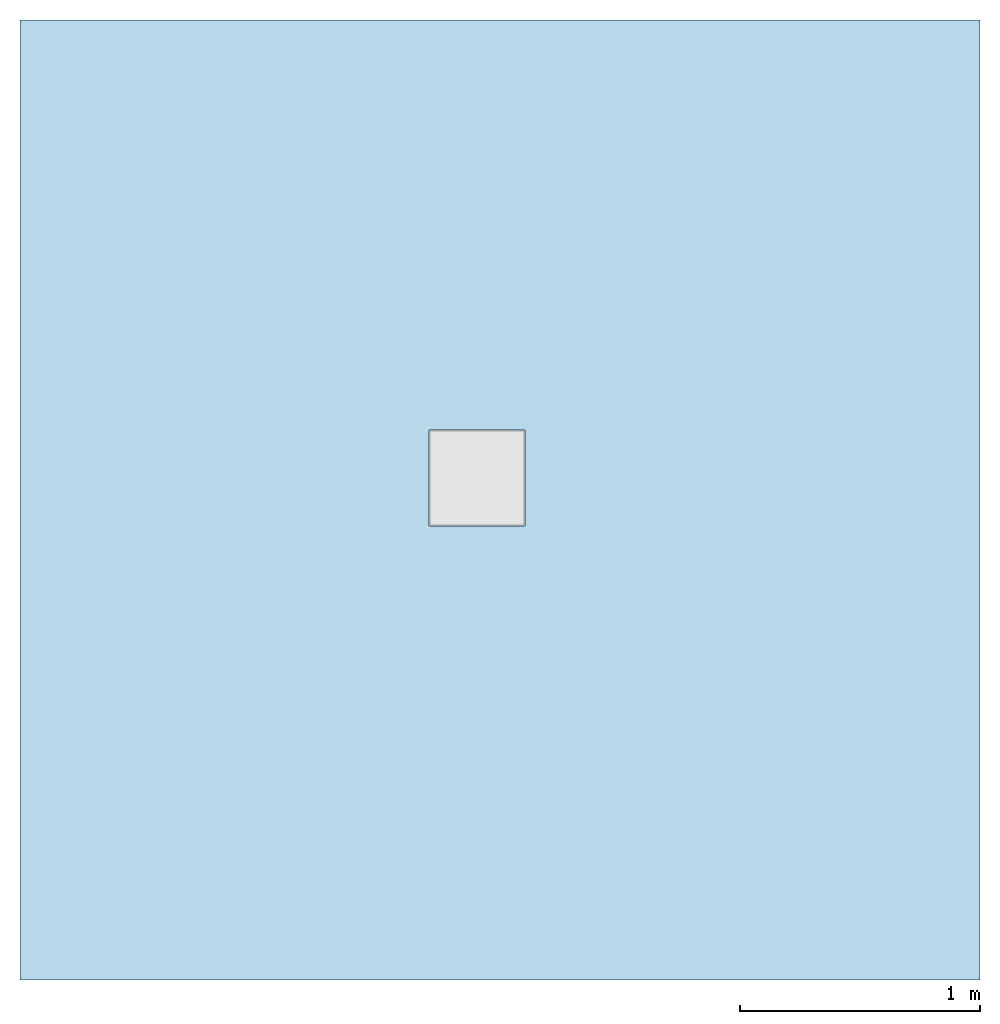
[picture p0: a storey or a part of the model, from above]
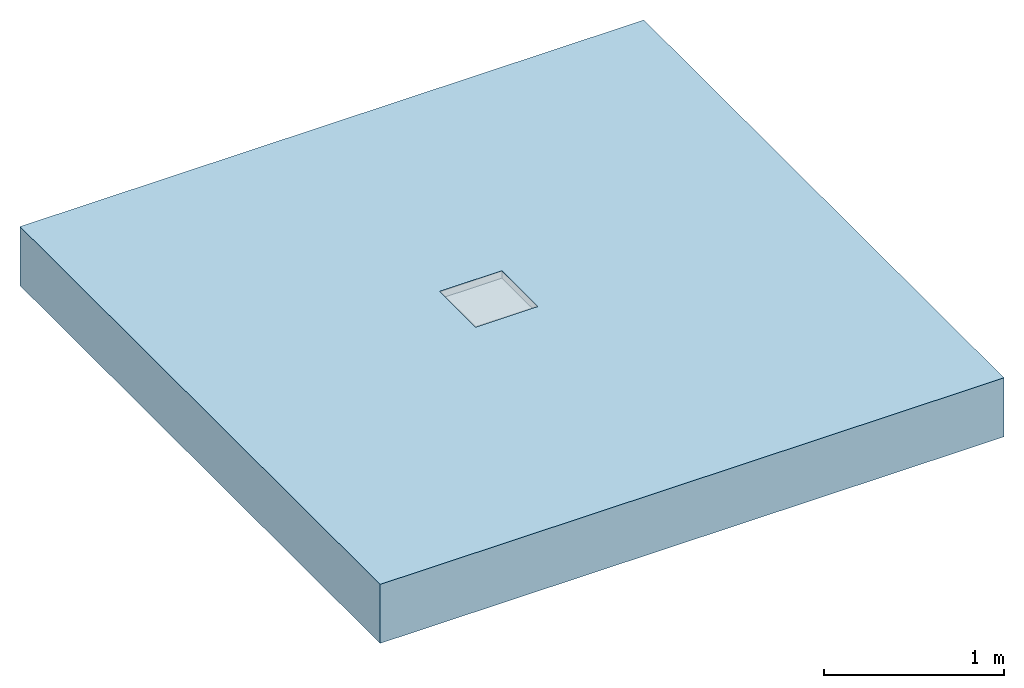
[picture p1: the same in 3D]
Properties of the parts of a building model (IFC2X3)

# File
Description: ViewDefinition [CoordinationView]
File name: Project Number
Time: 2014-06-06T10:56:56
Written by: The EXPRESS Data Manager Version 5.01.0100.02.64mod : 6 Jun 2012
Made in: 20130308_1515(x64) - Exporter 2014.0.2013.0308 - Default UI
Comment: STEP Physical File produced by: The EXPRESS Data Manager Version 5.01.0100.02.64mod : 6 Jun 2012 * Module: EDMstepFileFactory/EDMstandAlone * Creation date: Fri Jun 06 10:56:56 2014 * Host: IN-BLR-PC-0010 * Database: C:\Users\palleri\AppData\Local\Temp\{E2782E1B-111F-43A8-B7EB-C710C4CADA0F}\ifc * Database version: 5507 * Database creation date: Fri Jun 06 10:56:55 2014 * Schema: IFC2X3 * Model: DataRepository.ifc * Model creation date: Fri Jun 06 10:56:56 2014 * Header model: DataRepository.ifc_HeaderModel * Header model creation date: Fri Jun 06 10:56:56 2014 * EDMuser: sdai-user * EDMgroup: sdai-group * License ID and type: 5605 : Permanent license. Expiry date: * EDMstepFileFactory options: 020000

# IfcProject, Project Number
LongName: Project Name; Phase: Project Status

# IfcSite, Default
RefLatitude: 42, 21, 30, 344238; RefLongitude: -71, -3, -35, -194702; RefElevation: 0 mm

# IfcBuilding
Pset_BuildingCommon - NumberOfStoreys: 1
Other - Client Name: Owner; Project Name: Project Name; Project Status: Project Status; Project Address: ## Street City, State Zip; Project Issue Date: Issue Date; Project Number: Project Number

# IfcBuildingStorey, Level 1
LongName: Level 1; Elevation: 0 mm
Constraints - Elevation Base: Project Base Point; Elevation: 0 mm
Graphics - Color: 0; Symbol: M_Level Head - Circle: M_Level Head - Circle; Symbol at End 1 Default: no; Line Pattern: Center; Line Weight: 1; Symbol at End 2 Default: yes
Identity Data - Name: Level 1; Building Story: yes; Structural: no
Dimensions - Computation Height: 0 mm

# IfcFlowTerminal: 38150 - Access Frame - Fixed Height - Invert Depth 50mm, ACO Freedeck Access Frame & Drain Duct (Accessories part 1) V1.27 - GS:38150 - Access Frame - Fixed Height - Invert Depth 50mm:276243
In: Level 1
Material: Galvanized Steel
Dimensions - Top Void Height End: -50 mm; Height for Adjustable Access Frame: 105 mm; Drainage Duct – Level below FFL: 30 mm; Top Void Height Start: 2 mm; Total Height: 105 mm; Access Frame Extension Position Height: 5000 mm; Base Height: 3000 mm; Drain Duct End: -100 mm; Grating Start: 0 mm; Grating End: -20 mm
Construction - 36754_Access Grating_Mesh Grating_Galvanized Steel: yes; 38687_Access Frame Extension_Galvanized Steel_Invert Depth 75mm: no; 38685_Access Frame Extension_Galvanized Steel_Invert Depth 50mm: no
Phasing - Phase Created: New Construction
Identity Data - Mark: 14; E-mail Technical: abdtechnical@aco.co.uk; Watermark2: This file is water marked and users are prohibited to reproduce, adapt, distribute this information; Website: www.acobd.com; Watermarked By: www.acobd.com; E-mail Sales: abdcommercial@aco.co.uk; Watermark1: This file is the property of ACO Technologies PLC; Manufacturer: ACO Building Drainage; Watermarked With: BIM Manager Premium Suite; Telephone: +44 (0)1462 816666; Address: ACO Business Centre, Caxton Road, Bedford, MK41 0LF; Fax: +44 (0)1462 851490
Other - Access Frame Extension Height: 50 mm; Drain Duct Vertical Height: 5000 mm; Access Frame Extension: no; Extension Removal Void: -2 mm; Adjustable Access Frame Position Height: 105 mm; Access Frame Extension_Invert Depth 50mm: no; Fixed Access Frame Position Height: 50 mm; Access Frame Extension_Invert Depth 75mm: no; Drain Duct: no; Access Frame Fixed Height: yes; Access Frame Adjustable Height: no; Top void Size: 400 mm; Grating: yes
Constraints - Moves With Nearby Elements: no; Level: Level: Level 1
Pset_ManufacturerTypeInformation - Manufacturer: ACO Building Drainage
General - Product Description: ACO Freedeck Access Frame - Adjustable; NBS Specification: NBS Section R10 Gravity Rainwater Drainage Systems, Subsection 365; Channel Material: Hot Dipped Galvanised Steel; Product Type: Linear Deck Drainage System; Installation Guidelines: X:\Electronic Literature\ABD Electronic Literature\Roof and Balcony Drainage\ACO Freedeck Brochure.pdf; Channel Colour: Galvanised; Product Range: ACO Freedeck; Channel Recycled Material Content: 25 - 30 %; Channel Recyclable: Fully recyclable; Product Standard: BS EN 1433:2002, CE marked; Price: POA - contact ACO; Product Code: 38150; Load Class: A15; Weight (Kg): 5.7kg; Maintenance Guidelines: X:\Electronic Literature\ABD Electronic Literature\Roof and Balcony Drainage\ACO Freedeck Brochure.pdf; Dimensions (LxWxH): 400 x 400 x 50
Model Properties - Access Frame Extension Product Code 38687: Load Class A15 - Access Frame Extension - Galvanized Steel - Invert Depth 75mm - 1.9kg; Access Frame Extension Product Code 38686: N/A; Access Frame Extension Product Code 38688: N/A; Access Grating Product Code 36754: Load Class A15 - Mesh Grating - 14mm x 30mm Mesh - Galvanized Steel - 3.5kg; Access Frame Extension Product Code 38685: Load Class A15 - Access Frame Extension - Galvanized Steel - Invert Depth 50mm - 1.3kg; Access Grating Product Code 36760: N/A
Materials and Finishes - Material: Galvanized Steel

# IfcSlab: Floor:Generic Floor - 400mm, Floor:Generic Floor - 400mm:193825
In: Level 1
PredefinedType: FLOOR; Material: Concrete, Broom Finish 400 mm
Constraints - Level: Level: Level 1; Height Offset From Level: 0 mm; Room Bounding: yes; Related to Mass: no
Dimensions - Area: 16 m2; Thickness: 400 mm; Perimeter: 16000 mm; Volume: 6.392 m3
Phasing - Phase Created: New Construction
Structural - Structural: no; Enable Analytical Model: no
Pset_SlabCommon - Reference: Generic Floor - 400mm; IsExternal: no; LoadBearing: yes; ThermalTransmittance: 2.615 kg/K/s3; PitchAngle: 0 deg
Construction - Function: Interior; Default Thickness: 400 mm
Analytical Properties - Roughness: 1; Thermal Resistance (R): 0.382409; Absorptance: 0.1; Heat Transfer Coefficient (U): 2.615; Thermal mass: 604440
Graphics - Coarse Scale Fill Color: 0
Materials and Finishes - Structural Material: Concrete, Broom Finish
